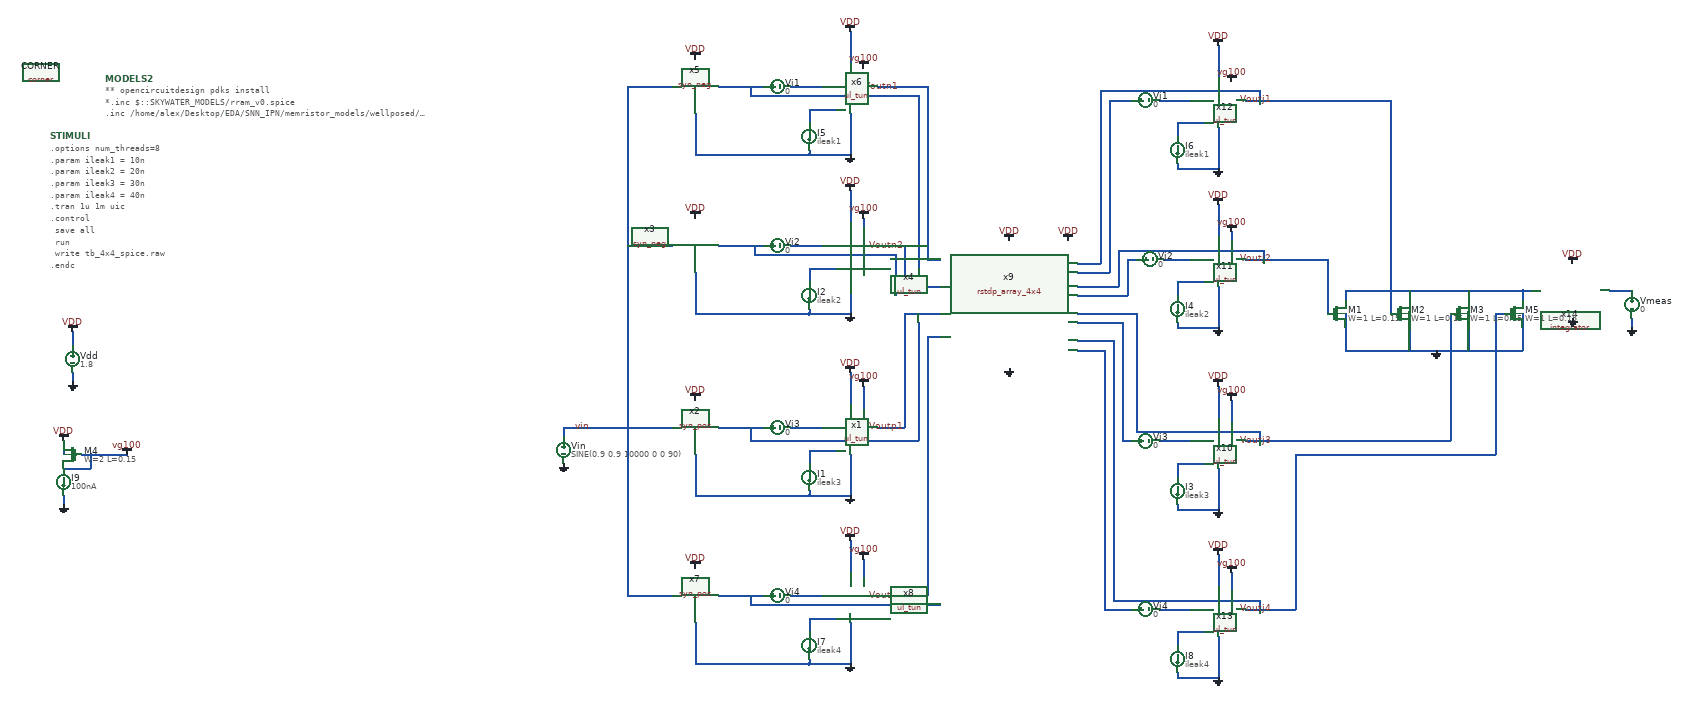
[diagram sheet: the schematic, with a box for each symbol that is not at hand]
v {xschem version=3.4.5 file_version=1.2
}
G {}
K {}
V {}
S {}
E {}
B 2 -930 -180 -130 220 {flags=graph
y1=-0.0024	
y2=7.3
ypos1=-0.00012
ypos2=3.7
divy=5
subdivy=1
unity=1
x1=5e-10
x2=0.0002
divx=5
subdivx=1


dataset=-1
unitx=1
logx=0
logy=0
digital=0
linewidth_mult=3.5
color="6 8 4 7"
node="\\"N1; voutn1 5.4 +\\"
\\"N2; voutn2 3.6 +\\"
\\"N3; voutp1 1.8 +\\"
\\"N4; voutp2\\""}
B 2 -890 -1170 -90 -770 {flags=graph
y1=0.001	
y2=1.8
ypos1=-0.319016
ypos2=2.49867
divy=5
subdivy=1
unity=1
x1=5e-10
x2=0.0002
divx=5
subdivx=1


dataset=-1
unitx=1
logx=0
logy=0
digital=0
linewidth_mult=3.5
color=6
node=vin}
B 2 -900 -750 -100 -350 {flags=graph
y1=1.8e-08	
y2=2.3e-07
ypos1=-0.319016
ypos2=2.49867
divy=5

unity=1
x1=5e-10
x2=0.0002
divx=5
subdivx=1


dataset=-1
unitx=1
logx=0
logy=0
digital=0
linewidth_mult=3.5
color="6 8 4 7"
node="i(vi1)
i(vi2)
i(vi3)
i(vi4)"
subdivy=2}
B 2 2380 -360 3180 40 {flags=graph
y1=-0.00043	
y2=7.3
ypos1=-0.00012
ypos2=3.7
divy=5
subdivy=1
unity=1
x1=5e-10
x2=0.0002
divx=5
subdivx=1


dataset=-1
unitx=1
logx=0
logy=0
digital=0
linewidth_mult=3.5
color="6 8 4 7"
node="\\"N1; voutj1 5.4 +\\"
\\"N2; voutj2 3.6 +\\"
\\"N3; voutj3 1.8 +\\"
\\"N4; voutj4\\""}
B 2 2380 -780 3180 -380 {flags=graph
y1=-2.5e-07	
y2=2.1e-05
ypos1=-0.00012
ypos2=3.7
divy=5
subdivy=1
unity=1
x1=5e-10
x2=0.0002
divx=5
subdivx=1


dataset=-1
unitx=1
logx=0
logy=0
digital=0
linewidth_mult=3.5

color=4
node=i(vmeas)}
B 2 2380 -1200 3180 -800 {flags=graph
y1=-7.204962e-08	
y2=1.2103502e-06
ypos1=-0.00012
ypos2=3.7
divy=5
subdivy=1
unity=1
x1=5e-10
x2=0.0002
divx=5
subdivx=1


dataset=-1
unitx=1
logx=0
logy=0
digital=0
linewidth_mult=3.5



color="6 8 4 7"
node="i(vj1)
i(vj2)
i(vj3)
i(vj4)"}
B 2 1000 -1720 1800 -1320 {flags=graph
y1=-0.13	
y2=2.2
ypos1=-0.00012
ypos2=3.7
divy=5
subdivy=1
unity=1
x1=5e-10
x2=0.0002
divx=5
subdivx=1


dataset=-1
unitx=1
logx=0
logy=0
digital=0
linewidth_mult=3.5




color="19 18 17 16 15 14 13 12 11 10 9 8 7 6 5 4"
node="x9.xrstdp16.xr2.r
x9.xrstdp15.xr2.r
x9.xrstdp14.xr2.r
x9.xrstdp13.xr2.r
x9.xrstdp12.xr2.r
x9.xrstdp11.xr2.r
x9.xrstdp10.xr2.r
x9.xrstdp9.xr2.r
x9.xrstdp8.xr2.r
x9.xrstdp7.xr2.r
x9.xrstdp6.xr2.r
x9.xrstdp5.xr2.r
x9.xrstdp4.xr2.r
x9.xrstdp3.xr2.r
x9.xrstdp2.xr2.r
x9.xrstdp1.xr2.r"}
N 500 -170 500 -160 {
lab=GND}
N -1120 -520 -1120 -490 {
lab=VDD}
N -1120 -430 -1120 -410 {
lab=GND}
N -40 -310 -40 -290 {
lab=vin}
N 590 -250 590 -160 {
lab=GND}
N 500 -160 590 -160 {
lab=GND}
N 590 -430 590 -360 {
lab=VDD}
N 650 -310 710 -310 {
lab=Voutp1}
N -40 -310 70 -310 {
lab=vin}
N 500 -260 560 -260 {
lab=#net1}
N 500 -260 500 -230 {
lab=#net1}
N 460 -310 530 -310 {
lab=#net2}
N 70 -310 200 -310 {
lab=vin}
N 250 -250 250 -160 {
lab=GND}
N 500 -570 500 -560 {
lab=GND}
N 590 -650 590 -560 {
lab=GND}
N 500 -560 590 -560 {
lab=GND}
N 590 -830 590 -760 {
lab=VDD}
N 650 -710 710 -710 {
lab=Voutn2}
N 500 -660 560 -660 {
lab=#net3}
N 500 -660 500 -630 {
lab=#net3}
N 460 -710 530 -710 {
lab=#net4}
N 500 -920 500 -910 {
lab=GND}
N 590 -1000 590 -910 {
lab=GND}
N 500 -910 590 -910 {
lab=GND}
N 590 -1180 590 -1110 {
lab=VDD}
N 650 -1060 710 -1060 {
lab=Voutn1}
N 500 -1010 560 -1010 {
lab=#net5}
N 500 -1010 500 -980 {
lab=#net5}
N 460 -1060 530 -1060 {
lab=#net6}
N 500 200 500 210 {
lab=GND}
N 590 120 590 210 {
lab=GND}
N 500 210 590 210 {
lab=GND}
N 590 -60 590 10 {
lab=VDD}
N 650 60 710 60 {
lab=Voutp2}
N 500 110 560 110 {
lab=#net7}
N 500 110 500 140 {
lab=#net7}
N 460 60 530 60 {
lab=#net8}
N 250 120 250 210 {
lab=GND}
N 100 -310 100 60 {
lab=vin}
N 100 -1060 100 -310 {
lab=vin}
N 100 -1060 200 -1060 {
lab=vin}
N 100 -710 200 -710 {
lab=vin}
N 100 60 200 60 {
lab=vin}
N 410 210 500 210 {
lab=GND}
N 410 -160 500 -160 {
lab=GND}
N -1140 -280 -1140 -250 {
lab=VDD}
N -1100 -250 -1080 -250 {
lab=vg100}
N -1140 -160 -1140 -140 {
lab=GND}
N -1080 -250 -1000 -250 {
lab=vg100}
N -1140 -220 -1080 -220 {
lab=vg100}
N -1080 -250 -1080 -220 {
lab=vg100}
N 620 -770 620 -750 {
lab=vg100}
N 620 -400 620 -350 {
lab=vg100}
N 620 -20 620 20 {
lab=vg100}
N 1310 -140 1310 -130 {
lab=GND}
N 1400 -220 1400 -130 {
lab=GND}
N 1310 -130 1400 -130 {
lab=GND}
N 1400 -400 1400 -330 {
lab=VDD}
N 1460 -280 1520 -280 {
lab=Voutj3}
N 1310 -230 1370 -230 {
lab=#net9}
N 1310 -230 1310 -200 {
lab=#net9}
N 1270 -280 1340 -280 {
lab=#net10}
N 1310 -540 1310 -530 {
lab=GND}
N 1400 -620 1400 -530 {
lab=GND}
N 1310 -530 1400 -530 {
lab=GND}
N 1400 -800 1400 -730 {
lab=VDD}
N 1460 -680 1520 -680 {
lab=Voutj2}
N 1310 -630 1370 -630 {
lab=#net11}
N 1310 -630 1310 -600 {
lab=#net11}
N 1310 -890 1310 -880 {
lab=GND}
N 1400 -970 1400 -880 {
lab=GND}
N 1310 -880 1400 -880 {
lab=GND}
N 1400 -1150 1400 -1080 {
lab=VDD}
N 1460 -1030 1520 -1030 {
lab=Voutj1}
N 1310 -980 1370 -980 {
lab=#net12}
N 1310 -980 1310 -950 {
lab=#net12}
N 1270 -1030 1340 -1030 {
lab=#net13}
N 1310 230 1310 240 {
lab=GND}
N 1400 150 1400 240 {
lab=GND}
N 1310 240 1400 240 {
lab=GND}
N 1400 -30 1400 40 {
lab=VDD}
N 1460 90 1520 90 {
lab=Voutj4}
N 1310 140 1370 140 {
lab=#net14}
N 1310 140 1310 170 {
lab=#net14}
N 1270 90 1340 90 {
lab=#net15}
N 1430 -740 1430 -720 {
lab=vg100}
N 1430 -370 1430 -320 {
lab=vg100}
N 1430 10 1430 50 {
lab=vg100}
N 760 -680 790 -680 {
lab=Voutn1}
N 760 -1060 760 -680 {
lab=Voutn1}
N 710 -620 790 -620 {
lab=Voutn2}
N 710 -710 710 -620 {
lab=Voutn2}
N 710 -560 790 -560 {
lab=Voutp1}
N 710 -560 710 -310 {
lab=Voutp1}
N 760 -510 790 -510 {
lab=Voutp2}
N 760 -510 760 60 {
lab=Voutp2}
N 740 -1040 740 -660 {
lab=#net16}
N 370 -1060 370 -1040 {
lab=#net16}
N 690 -690 690 -600 {
lab=#net17}
N 370 -310 370 -280 {
lab=#net18}
N 370 60 370 80 {
lab=#net19}
N 1490 -1050 1490 -1030 {
lab=Voutj1}
N 1140 -1050 1490 -1050 {
lab=Voutj1}
N 1140 -1050 1140 -670 {
lab=Voutj1}
N 1090 -670 1140 -670 {
lab=Voutj1}
N 1500 -700 1500 -680 {
lab=Voutj2}
N 1150 -480 1150 90 {
lab=#net20}
N 1090 -480 1150 -480 {
lab=#net20}
N 1490 70 1490 90 {
lab=Voutj4}
N 1170 70 1490 70 {
lab=Voutj4}
N 1170 -500 1170 70 {
lab=Voutj4}
N 1090 -500 1170 -500 {
lab=Voutj4}
N 1090 -540 1190 -540 {
lab=#net21}
N 1190 -540 1190 -280 {
lab=#net21}
N 1490 -300 1490 -280 {
lab=Voutj3}
N 1220 -300 1490 -300 {
lab=Voutj3}
N 1220 -560 1220 -300 {
lab=Voutj3}
N 1090 -560 1220 -560 {
lab=Voutj3}
N 1200 -680 1200 -600 {
lab=#net22}
N 1250 -700 1500 -700 {
lab=Voutj2}
N 1180 -700 1180 -620 {
lab=Voutj2}
N 1090 -650 1160 -650 {
lab=#net23}
N 1160 -1030 1160 -650 {
lab=#net23}
N 1680 -610 1680 -590 {
lab=#net24}
N 1680 -610 2070 -610 {
lab=#net24}
N 2070 -610 2070 -590 {
lab=#net24}
N 1820 -610 1820 -590 {
lab=#net24}
N 1950 -610 1950 -590 {
lab=#net24}
N 1880 -480 2070 -480 {
lab=GND}
N 2070 -530 2070 -480 {
lab=GND}
N 1950 -530 1950 -480 {
lab=GND}
N 1680 -480 1880 -480 {
lab=GND}
N 1680 -530 1680 -480 {
lab=GND}
N 1820 -530 1820 -480 {
lab=GND}
N 1680 -560 1680 -530 {
lab=GND}
N 1820 -560 1820 -530 {
lab=GND}
N 1950 -560 1950 -530 {
lab=GND}
N 2070 -560 2070 -530 {
lab=GND}
N 2070 -610 2090 -610 {
lab=#net24}
N 1520 -280 1910 -280 {
lab=Voutj3}
N 1910 -560 1910 -280 {
lab=Voutj3}
N 1640 -680 1640 -560 {
lab=Voutj2}
N 1520 -680 1640 -680 {
lab=Voutj2}
N 1780 -1030 1780 -560 {
lab=Voutj1}
N 1520 -1030 1780 -1030 {
lab=Voutj1}
N 2010 -560 2030 -560 {
lab=Voutj4}
N 2010 -560 2010 -250 {
lab=Voutj4}
N 1570 -250 2010 -250 {
lab=Voutj4}
N 1570 -250 1570 90 {
lab=Voutj4}
N 1520 90 1570 90 {
lab=Voutj4}
N 2260 -610 2310 -610 {
lab=#net25}
N 2310 -550 2310 -530 {
lab=GND}
N 410 -910 500 -910 {
lab=GND}
N 250 -1000 250 -910 {
lab=GND}
N 410 -560 500 -560 {
lab=GND}
N 250 -650 250 -560 {
lab=GND}
N 1160 -1030 1210 -1030 {
lab=#net23}
N 1090 -620 1180 -620 {
lab=Voutj2}
N 1180 -700 1250 -700 {
lab=Voutj2}
N 1200 -680 1220 -680 {
lab=#net22}
N 1280 -680 1340 -680 {
lab=#net26}
N 1090 -600 1200 -600 {
lab=#net22}
N 1190 -280 1210 -280 {
lab=#net21}
N 1150 90 1210 90 {
lab=#net20}
N 710 -1060 760 -1060 {
lab=Voutn1}
N 250 -910 410 -910 {
lab=GND}
N 300 -1060 400 -1060 {
lab=#net16}
N 300 -710 400 -710 {
lab=#net17}
N 250 -560 410 -560 {
lab=GND}
N 710 60 760 60 {
lab=Voutp2}
N 250 210 410 210 {
lab=GND}
N 250 -160 410 -160 {
lab=GND}
N 300 -310 400 -310 {
lab=#net18}
N 300 60 400 60 {
lab=#net19}
N 370 -1040 740 -1040 {
lab=#net16}
N 380 -690 690 -690 {
lab=#net17}
N 380 -710 380 -690 {
lab=#net17}
N 370 -280 740 -280 {
lab=#net18}
N 740 -540 740 -280 {
lab=#net18}
N 370 80 790 80 {
lab=#net19}
C {devices/isource.sym} 500 -200 0 0 {name=I1 value=ileak3}
C {devices/gnd.sym} 590 -160 0 0 {name=l3 lab=GND}
C {devices/lab_pin.sym} 710 -310 1 1 {name=p2 sig_type=std_logic lab=Voutp1
}
C {devices/vsource.sym} -1120 -460 0 0 {name=Vdd value=1.8}
C {devices/gnd.sym} -1120 -410 0 0 {name=l5 lab=GND}
C {sky130_fd_pr/corner.sym} -1190 -1090 0 0 {name=CORNER only_toplevel=true corner=tt}
C {devices/code_shown.sym} -1170 -950 0 0 {name=STIMULI 
only_toplevel=true
place=end
value="
.options num_threads=8
.param ileak1 = 10n
.param ileak2 = 20n
.param ileak3 = 30n
.param ileak4 = 40n
.tran 1u 1m uic
.control
	save all
	run
	write tb_4x4_spice.raw
.endc
"}
C {devices/vdd.sym} -1120 -520 0 0 {nname=l4 lab=VDD}
C {devices/vdd.sym} 590 -430 0 0 {name=l7 lab=VDD}
C {devices/launcher.sym} -1090 -655 0 0 {name=h5
descr="load waves" 
tclcommand="xschem raw_read $netlist_dir/tb_4x4_spice.raw tran"
q}
C {devices/vsource.sym} -40 -260 0 0 {name=Vin value="SINE(0.9 0.9 10000 0 0 90)"}
C {devices/lab_pin.sym} 20 -310 1 1 {name=p1 sig_type=std_logic lab=vin
}
C {/home/alex/Desktop/EDA/SNN_IPN/Neuron/ultralif/syn_pos.sym} 250 -390 0 0 {name=x2}
C {/home/alex/Desktop/EDA/SNN_IPN/Neuron/ultralif/ul_tun.sym} 590 -310 0 0 {name=x1}
C {devices/vdd.sym} 250 -370 0 0 {nname=l4 lab=VDD}
C {devices/isource.sym} 500 -600 0 0 {name=I2 value=ileak2}
C {devices/gnd.sym} 590 -560 0 0 {name=l6 lab=GND}
C {devices/lab_pin.sym} 710 -710 3 1 {name=p3 sig_type=std_logic lab=Voutn2
}
C {devices/vdd.sym} 590 -830 0 0 {name=l9 lab=VDD}
C {/home/alex/Desktop/EDA/SNN_IPN/Neuron/ultralif/syn_neg.sym} 250 -790 0 0 {name=x3}
C {/home/alex/Desktop/EDA/SNN_IPN/Neuron/ultralif/ul_tun.sym} 590 -710 0 0 {name=x4}
C {devices/vdd.sym} 250 -770 0 0 {nname=l4 lab=VDD}
C {devices/isource.sym} 500 -950 0 0 {name=I5 value=ileak1}
C {devices/gnd.sym} 590 -910 0 0 {name=l1 lab=GND}
C {devices/lab_pin.sym} 700 -1060 3 1 {name=p4 sig_type=std_logic lab=Voutn1
}
C {devices/vdd.sym} 590 -1180 0 0 {name=l8 lab=VDD}
C {/home/alex/Desktop/EDA/SNN_IPN/Neuron/ultralif/syn_neg.sym} 250 -1140 0 0 {name=x5}
C {/home/alex/Desktop/EDA/SNN_IPN/Neuron/ultralif/ul_tun.sym} 590 -1060 0 0 {name=x6}
C {devices/vdd.sym} 250 -1120 0 0 {nname=l4 lab=VDD}
C {devices/isource.sym} 500 170 0 0 {name=I7 value=ileak4}
C {devices/gnd.sym} 590 210 0 0 {name=l14 lab=GND}
C {devices/lab_pin.sym} 710 60 3 1 {name=p5 sig_type=std_logic lab=Voutp2
}
C {devices/vdd.sym} 590 -60 0 0 {name=l15 lab=VDD}
C {/home/alex/Desktop/EDA/SNN_IPN/Neuron/ultralif/syn_pos.sym} 250 -20 0 0 {name=x7}
C {/home/alex/Desktop/EDA/SNN_IPN/Neuron/ultralif/ul_tun.sym} 590 60 0 0 {name=x8}
C {devices/vdd.sym} 250 0 0 0 {nname=l4 lab=VDD}
C {devices/gnd.sym} -40 -230 0 0 {name=l18 lab=GND}
C {devices/isource.sym} -1140 -190 0 0 {name=I9 value=100nA

spice_ignore=false}
C {devices/vdd.sym} -1140 -280 0 0 {name=l19 lab=VDD}
C {sky130_fd_pr/pfet_01v8.sym} -1120 -250 0 1 {name=M4
L=0.15
W=2
nf=1
mult=1
model=pfet_01v8
spiceprefix=X
}
C {devices/gnd.sym} -1140 -140 0 0 {name=l20 lab=GND}
C {devices/vdd.sym} -1000 -250 0 0 {name=l21 lab=vg100}
C {devices/vdd.sym} 620 -1100 0 0 {name=l22 lab=vg100}
C {devices/vdd.sym} 620 -770 0 0 {name=l10 lab=vg100}
C {devices/vdd.sym} 620 -400 0 0 {name=l2 lab=vg100}
C {devices/vdd.sym} 620 -20 0 0 {name=l4 lab=vg100}
C {/home/alex/Desktop/EDA/SNN_IPN/Synapse/rstdp_array_4x4.sym} 940 -510 0 0 {name=x9}
C {devices/isource.sym} 1310 -170 0 0 {name=I3 value=ileak3}
C {devices/gnd.sym} 1400 -130 0 0 {name=l11 lab=GND}
C {devices/lab_pin.sym} 1520 -280 1 1 {name=p6 sig_type=std_logic lab=Voutj3
}
C {devices/vdd.sym} 1400 -400 0 0 {name=l12 lab=VDD}
C {/home/alex/Desktop/EDA/SNN_IPN/Neuron/ultralif/ul_tun.sym} 1400 -280 0 0 {name=x10}
C {devices/isource.sym} 1310 -570 0 0 {name=I4 value=ileak2}
C {devices/gnd.sym} 1400 -530 0 0 {name=l13 lab=GND}
C {devices/lab_pin.sym} 1520 -680 1 1 {name=p7 sig_type=std_logic lab=Voutj2
}
C {devices/vdd.sym} 1400 -800 0 0 {name=l16 lab=VDD}
C {/home/alex/Desktop/EDA/SNN_IPN/Neuron/ultralif/ul_tun.sym} 1400 -680 0 0 {name=x11}
C {devices/isource.sym} 1310 -920 0 0 {name=I6 value=ileak1}
C {devices/gnd.sym} 1400 -880 0 0 {name=l17 lab=GND}
C {devices/lab_pin.sym} 1520 -1030 1 1 {name=p8 sig_type=std_logic lab=Voutj1
}
C {devices/vdd.sym} 1400 -1150 0 0 {name=l23 lab=VDD}
C {/home/alex/Desktop/EDA/SNN_IPN/Neuron/ultralif/ul_tun.sym} 1400 -1030 0 0 {name=x12}
C {devices/isource.sym} 1310 200 0 0 {name=I8 value=ileak4}
C {devices/gnd.sym} 1400 240 0 0 {name=l24 lab=GND}
C {devices/vdd.sym} 1400 -30 0 0 {name=l25 lab=VDD}
C {/home/alex/Desktop/EDA/SNN_IPN/Neuron/ultralif/ul_tun.sym} 1400 90 0 0 {name=x13}
C {devices/vdd.sym} 1430 -1070 0 0 {name=l26 lab=vg100}
C {devices/vdd.sym} 1430 -740 0 0 {name=l27 lab=vg100}
C {devices/vdd.sym} 1430 -370 0 0 {name=l28 lab=vg100}
C {devices/vdd.sym} 1430 10 0 0 {name=l29 lab=vg100}
C {devices/gnd.sym} 940 -440 0 0 {name=l30 lab=GND}
C {devices/vdd.sym} 940 -720 0 0 {name=l31 lab=VDD}
C {devices/lab_pin.sym} 1520 90 1 1 {name=p10 sig_type=std_logic lab=Voutj4
}
C {devices/vdd.sym} 1070 -720 0 0 {name=l39 lab=VDD}
C {/home/alex/Desktop/EDA/SNN_IPN/Neuron/ultralif/integrator.sym} 2110 -610 0 0 {name=x14}
C {sky130_fd_pr/nfet_01v8.sym} 1660 -560 0 0 {name=M1
L=0.15
W=1
nf=1 
mult=1
ad="'int((nf+1)/2) * W/nf * 0.29'" 
pd="'2*int((nf+1)/2) * (W/nf + 0.29)'"
as="'int((nf+2)/2) * W/nf * 0.29'" 
ps="'2*int((nf+2)/2) * (W/nf + 0.29)'"
nrd="'0.29 / W'" nrs="'0.29 / W'"
sa=0 sb=0 sd=0
model=nfet_01v8
spiceprefix=X
}
C {sky130_fd_pr/nfet_01v8.sym} 1800 -560 0 0 {name=M2
L=0.15
W=1
nf=1 
mult=1
ad="'int((nf+1)/2) * W/nf * 0.29'" 
pd="'2*int((nf+1)/2) * (W/nf + 0.29)'"
as="'int((nf+2)/2) * W/nf * 0.29'" 
ps="'2*int((nf+2)/2) * (W/nf + 0.29)'"
nrd="'0.29 / W'" nrs="'0.29 / W'"
sa=0 sb=0 sd=0
model=nfet_01v8
spiceprefix=X
}
C {sky130_fd_pr/nfet_01v8.sym} 1930 -560 0 0 {name=M3
L=0.15
W=1
nf=1 
mult=1
ad="'int((nf+1)/2) * W/nf * 0.29'" 
pd="'2*int((nf+1)/2) * (W/nf + 0.29)'"
as="'int((nf+2)/2) * W/nf * 0.29'" 
ps="'2*int((nf+2)/2) * (W/nf + 0.29)'"
nrd="'0.29 / W'" nrs="'0.29 / W'"
sa=0 sb=0 sd=0
model=nfet_01v8
spiceprefix=X
}
C {sky130_fd_pr/nfet_01v8.sym} 2050 -560 0 0 {name=M5
L=0.15
W=1
nf=1 
mult=1
ad="'int((nf+1)/2) * W/nf * 0.29'" 
pd="'2*int((nf+1)/2) * (W/nf + 0.29)'"
as="'int((nf+2)/2) * W/nf * 0.29'" 
ps="'2*int((nf+2)/2) * (W/nf + 0.29)'"
nrd="'0.29 / W'" nrs="'0.29 / W'"
sa=0 sb=0 sd=0
model=nfet_01v8
spiceprefix=X
}
C {devices/gnd.sym} 1880 -480 0 0 {name=l32 lab=GND}
C {devices/vdd.sym} 2180 -670 0 0 {name=l33 lab=VDD}
C {devices/gnd.sym} 2180 -550 0 0 {name=l34 lab=GND}
C {devices/vsource.sym} 2310 -580 0 0 {name=Vmeas value=0}
C {devices/gnd.sym} 2310 -530 0 0 {name=l35 lab=GND}
C {devices/code.sym} -1047.5 -1077.5 0 0 {name=MODELS2
only_toplevel=true
format="tcleval( @value )"
value="
** opencircuitdesign pdks install
*.inc $::SKYWATER_MODELS/rram_v0.spice
.inc /home/alex/Desktop/EDA/SNN_IPN/memristor_models/wellposed/wllpsd.spice

"
spice_ignore=false}
C {devices/vsource.sym} 1240 -1030 3 0 {name=Vj1 value=0}
C {devices/vsource.sym} 1250 -680 3 0 {name=Vj2 value=0}
C {devices/vsource.sym} 1240 -280 3 0 {name=Vj3 value=0}
C {devices/vsource.sym} 1240 90 3 0 {name=Vj4 value=0}
C {devices/vsource.sym} 430 -1060 3 0 {name=Vi1 value=0}
C {devices/vsource.sym} 430 -710 3 0 {name=Vi2 value=0}
C {devices/vsource.sym} 430 -310 3 0 {name=Vi3 value=0}
C {devices/vsource.sym} 430 60 3 0 {name=Vi4 value=0}
